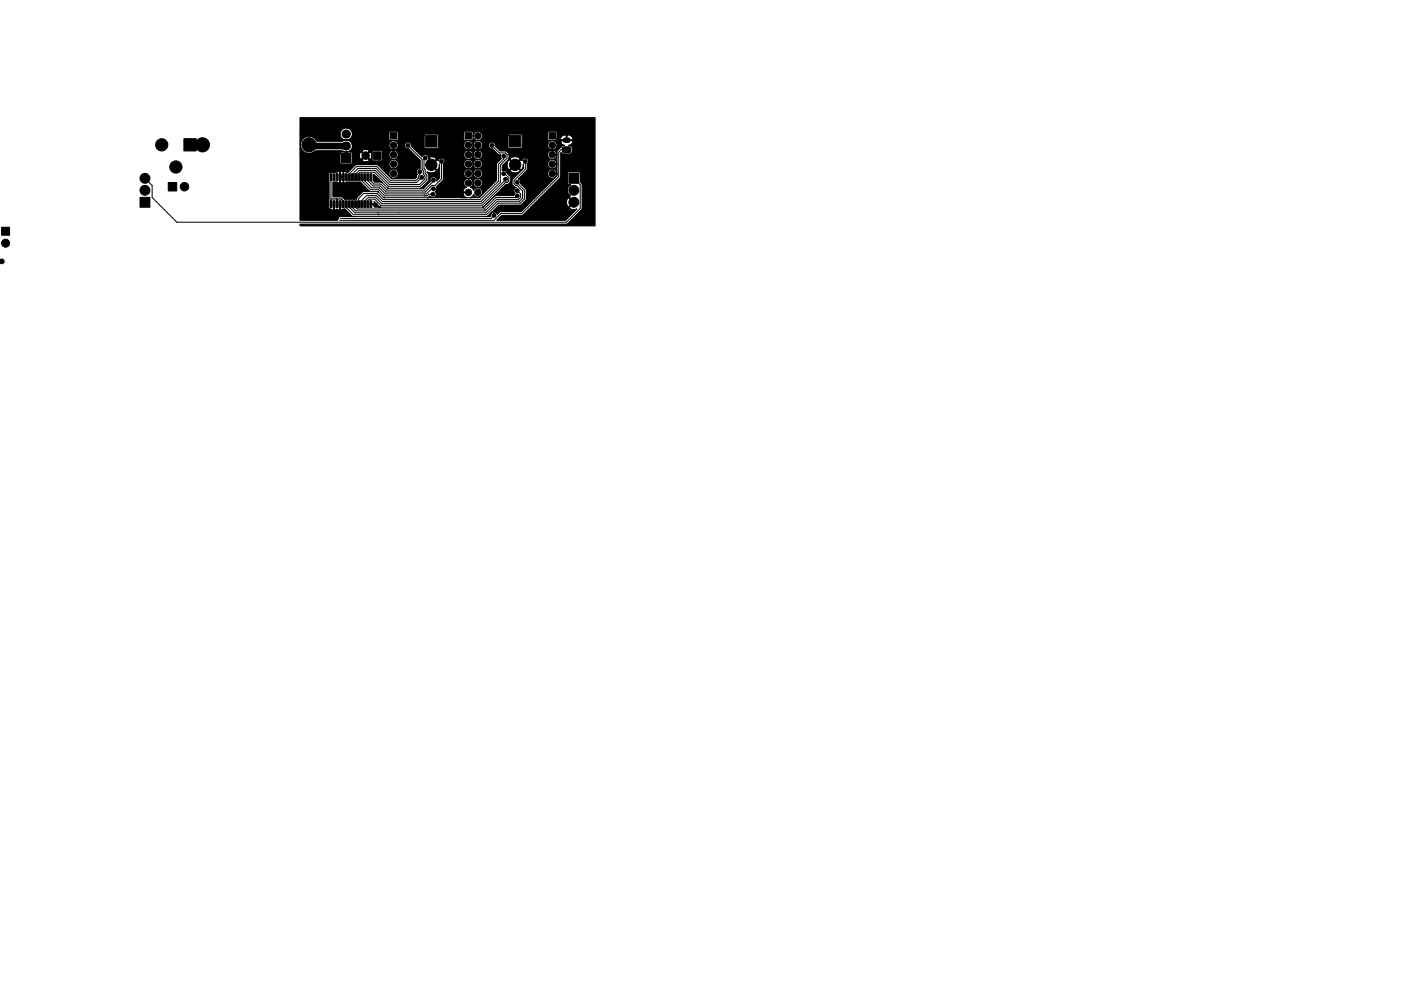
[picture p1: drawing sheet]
<svg xmlns="http://www.w3.org/2000/svg" width="297mm" height="210mm" viewBox="0 0 297 210" stroke-linecap="round" stroke-linejoin="round" font-family="sans-serif">
<g fill="#000" stroke="#000" stroke-width=".21">
<path d="M39 29.4h2.6v2.6h-2.6zM70 36.9h.4l-.1 1.4-.3-.1zM70.7 36.9h.3l-.1 1.4-.3-.1zM71.3 36.9h.4l-.1 1.4-.3-.1zM72 36.9h.3l-.1 1.4-.3-.1zM72.6 36.9h.4l-.1 1.4-.3-.1zM73.3 36.9h.3l-.1 1.4-.3-.1zM73.9 36.9h.4l-.1 1.4-.3-.1zM72.4 32.6h2v1.9h-2zM74.6 36.9h.3l-.1 1.4-.3-.1zM75.2 36.9h.4l-.1 1.4-.3-.1zM75.9 36.9h.3l-.1 1.4-.3-.1z"/>
<path d="M76.5 36.9h.4l-.1 1.4-.3-.1zM77.2 36.9h.3l-.1 1.4-.3-.1zM77.8 36.9h.4l-.1 1.4-.3-.1zM78.5 36.9h.3l-.1 1.4-.3-.1zM79.2 32.2h1.6v1.6h-1.6zM79.1 36.9l1.9 1.9-1.6-.2-.3-.3zM82.1 39.8l.3 .1zM82.8 28.1h1.3v1.4h-1.3zM90.2 28.8h2.4v2.4h-2.4zM98.6 28.1h1.4v1.4h-1.4zM108 28.8h2.4v2.4h-2.4zM116.4 28.1h1.4v1.4h-1.4z"/>
<path d="M120.6 36.8h2.1v2.1h-2.1zM119.3 31.2h1.6l.1 1-1.6 .1zM.3 48.2h1.7v1.7h-1.7zM29.7 41.9h2.1v2.1h-2.1zM35.7 38.7h1.8v1.8h-1.8zM70 42.6l.4 .1-.1 1.3h-.3zM70.7 42.6l.3 .1-.1 1.3h-.3zM71.3 42.6l.4 .1-.1 1.3h-.3zM72 42.6l.3 .1-.1 1.3h-.3zM72.6 42.6l.4 .1-.1 1.3h-.3zM73.3 42.6l.3 .1-.1 1.3h-.3zM73.9 42.6l.4 .1-.1 1.3h-.3z"/>
<path d="M74.6 42.6l.3 .1-.1 1.3h-.3zM75.2 42.6l.4 .1-.1 1.3h-.3zM75.9 42.6l.3 .1-.1 1.3h-.3zM76.5 42.6l.4 .1-.1 1.3h-.3zM77.2 42.6l.3 .1-.1 1.3h-.3zM77.8 42.6l.4 .1-.1 1.3h-.3zM78.5 42.6l.3 .1-.1 1.3h-.3zM80 40.6l.2 .2zM78.5 43.2h.7l.1-.5 1.4 1.2h-1.4l-.1-.5h-.7zM81.3 41.8l.2 .1zM63.6 25h62.6v22.9h-62.6v-.4h56.6l3.2-3.2v-5.1l-.4-.6v-1.8l-.1-.3h-2.3l-.2 .1-.1 2.3 .2 .3h.5l-.2 .1a1.35 1.35 0 0 0 .2 2.2l-.3 .3 1.1 1.1-1.1 1.1a1.23 1.23 0 0 0 1.6 .3l-2.4 2.4h-14.6l1.1-1h4.4l2.7-2.7h6.6l.1 .6 .4 .3 .9-1-.9-.9-.4 .4-.1 .6h-6.6l5.3-5.4 .1-5.2 .1-.1 .5 .3h1.5l.3-.4v-.8a.6 .6 0 0 0-.8-.6 .85 .85 0 0 0 .9-1h-2.5l-.1 .2 .2 .5 .8 .3-.6 .1-1.1 1.3v5.1l-7.6 7.6h-4.4l-.7 .6a.7 .7 0 0 0-.8-.5 .7 .7 0 0 0-.5 .8l-.9 .1 2.6-2.4h4.6l1.1-1 .1-.3v-2l-1.3-1.3a.7 .7 0 0 0-.4-.9l1.2-1.3h5a.98 .98 0 0 0 1.3 1 .98 .98 0 0 0 .4-1.6 .98 .98 0 0 0-1.6 .4l-.1 .2h-5l.7-.6 .1-1.4h4.2a.98 .98 0 0 0 1.3 1 .98 .98 0 0 0 .4-1.6 .98 .98 0 0 0-1.6 .4l-.1 .2h-4.2a.7 .7 0 0 0-.2-1.1 .7 .7 0 0 0-1 .5l-.3-.2-1 1.1 1 1a1.12 1.12 0 0 0 .5-1.2l.1 .9-2.4 2.5v1l.5 .5 .4 .1a.7 .7 0 0 0-.3 1.2l-.2 .5h-4l-2.5 2.4h-.2l5-4.8h.4l.5-.5v-1.1l-1-1.2-.3-.1h1.3a1.31 1.31 0 0 0 2.1 0l-1.1-1.1-1 1.1h-1.7v-1l.2-.2h.8a1.02 1.02 0 0 0 .5 1l1.1-1-1.1-1.1a1.09 1.09 0 0 0-.5 1.1h-.8l1.2-1.2h.3l1 1 1.1-1a1.31 1.31 0 0 0-2.1 0h-.3v-1.1h8.2a.98 .98 0 0 0 1.3 1 .98 .98 0 0 0 .4-1.6 .98 .98 0 0 0-1.6 .4l-.1 .2h-8.2l-.6-.6-1.3-.1-1-1a.7 .7 0 0 0-.7-.8 .7 .7 0 0 0-.7 .7 .7 .7 0 0 0 .8 .6l1.2 1.3h.6l-.1 .4 .2 .4-1 1.2v3.5l-3.7 3.6h-2l.8-.6a.98 .98 0 0 0 1.6 .3 .98 .98 0 0 0-.1-1.6 .98 .98 0 0 0-1.5 .4l-.2-.4-.5-.3a1.12 1.12 0 0 0 .6-1 .98 .98 0 0 0 1.4 1 .98 .98 0 0 0 .3-1.6 .98 .98 0 0 0-1.6 .4l-.1 .2a.98 .98 0 0 0-1.6-.7 .98 .98 0 0 0 .2 1.7l-.5 .3-.2 .5 .1 .2h1.1v.2h-1.1l-.1 .2 .2 .5 .6 .3h-8.4l.5-.3h.2a.7 .7 0 0 0 1 .1 .7 .7 0 0 0-.1-1 .88 .88 0 0 0 .3-1.1l1.5-1.5v-1.4h4.3a.98 .98 0 0 0 1 1.1 .98 .98 0 0 0 1-1.1 1.1 1.1 0 0 0 .9 1.1 .99 .99 0 0 0 1.1-.9 .99 .99 0 0 0-.9-1.1 .99 .99 0 0 0-1.1 .9 .98 .98 0 0 0-1-.9 .98 .98 0 0 0-1 .9h-4.3v-1.9l4.3-.1v.2a.98 .98 0 0 0 1.1 .9 .98 .98 0 0 0 .9-1.1 1.1 1.1 0 0 0 .9 1.1 .99 .99 0 0 0 1.1-.9 .99 .99 0 0 0-.9-1.1 .99 .99 0 0 0-1.1 .9 .98 .98 0 0 0-1-.9 .98 .98 0 0 0-1 .9h-4.2a.7 .7 0 0 0-.2-1.1 .7 .7 0 0 0-1 .5l-.3-.2-1 1.1 1 1a1.12 1.12 0 0 0 .5-1.2l.1 3-.6 .6a.7 .7 0 0 0-.7-.9 .7 .7 0 0 0-.6 1l-1.5 1.4h-.7l1.8-1.6v-1.2l-.4-.7 .6 .2h.7l.6-.2 .1-.2-1.2-1.2 1.2-1.2-.1-.3-.7-.2h-.9a.7 .7 0 0 0-.6-.5 .7 .7 0 0 0-.7 .5l-.6-.6h9.4a.98 .98 0 0 0 1 1.1 .98 .98 0 0 0 1-1.1 1.1 1.1 0 0 0 .9 1.1 .99 .99 0 0 0 1.1-.9 .99 .99 0 0 0-.9-1.1 .99 .99 0 0 0-1.1 .9 .98 .98 0 0 0-1-.9 .98 .98 0 0 0-1 .9h-9.4l-1.7-1.7a.7 .7 0 0 0-.7-.8 .7 .7 0 0 0-.7 .7 .7 .7 0 0 0 .8 .6l2.5 2.5v1.8a.7 .7 0 0 0-.7 .3 .7 .7 0 0 0 .1 .9l-.2 .2v.4l-.3 .3h-4.9l-1.3-1.2h.7v.2a.98 .98 0 0 0 1.5 .8 .98 .98 0 0 0 0-1.7 .98 .98 0 0 0-1.5 .7h-.7l-1.9-1.8-4.4 .1-1.8 1.6-.7-.3-.1 .2v2.2l.1 .1 .7-.2h2.6l2.3 2-1.7 .1-1.2 1.2-.1 .4h-2.5l-.7-.5h-1.8v-3.2h.5l.8 .2 .2-.5a.39 .39 0 0 0 .3 .5 .39 .39 0 0 0 .4-.5l-.1-.6h-.5l-.2 .6v-.6v-.8l.2 .6h.5l.1-.7a.38 .38 0 0 0-.4-.4 .38 .38 0 0 0-.3 .5l-.2-.6-.8 .3h-1.1l-.3 .3v7.1l.2 .3 .7 .2 .1-.1v-1.2h.2v1.2l.3 .1a.41 .41 0 0 1 .7 0l.1-.1v-1.2h.2v1.2l.2 .1 .7-.2 1.8 1.6-2.8 .1-.3 .1-.2 .6h-8v-14.1h8.5v1.9l.2 .3 10.2-.1a.98 .98 0 0 0 1.3 1 .98 .98 0 0 0 .3-1.6 .98 .98 0 0 0-1.6 .4v.2h-7.9l.1-.8h2a.92 .92 0 0 0 1.6 0l-.8-.7-.8 .7h-2v-.8h1.5l.2 .6 .2 .1 .8-.8h.3l.7 .8a.92 .92 0 0 0 0-1.5l-.7 .7h-.3l-.8-.7h-.2l-.2 .8h-1.5v-.6l-.3-.2h-2.1l-.2 .3h-8.5v-2h.1v.3a1.8 1.8 0 0 0 1.2 1.5 1.8 1.8 0 0 0 1.9-.4h5.8l.7 .2 3.4-.1 .8 .8 .7-.7h.7v1.7l.3 .2h1.8l.1-.2v-1.2h1.4v.2a.98 .98 0 0 0 1.5 .8 .98 .98 0 0 0 0-1.7 .98 .98 0 0 0-1.5 .7h-1.4v-.6l-.3-.2h-1.6l-.3 .3h-.7v-.3l-.7-.2-.7 .2-.1 .2h-2.7a1.25 1.25 0 0 0 .7-1.4h7.8v.2a.98 .98 0 0 0 1.5 .8 .98 .98 0 0 0 0-1.7 .98 .98 0 0 0-1.5 .7h-7.8l-.1-.2a1.33 1.33 0 0 0-2-.5l-5.5-.1a1.81 1.81 0 0 0-1.9-.9 1.81 1.81 0 0 0-1.5 1.6h-.1v-2.2h8.5v.3a1.3 1.3 0 0 0 1.6 1 1.3 1.3 0 0 0 1-1.6h7.8v1.5l.3 .2 1.5-.1 .1-.9h5.5v2.4l.3 .3h2.5l.2-.2v-.6h5.4v.2a.98 .98 0 0 0 1.1 .9 .98 .98 0 0 0 .9-1.1 1.1 1.1 0 0 0 .9 1.1 .99 .99 0 0 0 1.1-.9 .99 .99 0 0 0-.9-1.1 .99 .99 0 0 0-1.1 .9 .98 .98 0 0 0-1-.9 .98 .98 0 0 0-1 .9h-5.4v-2l-.2-.2h-2.5l-.3 .3h-5.5v-.7h13.9v1.5l.3 .2 1.6-.1 .1-1a.98 .98 0 0 0 1 1.1 .98 .98 0 0 0 1-1h5.4v2.4l.3 .3h2.5l.2-.2v-.6h5.4v.2a.98 .98 0 0 0 1.5 .8 .98 .98 0 0 0 0-1.7 .98 .98 0 0 0-1.5 .7h-5.4v-2l-.2-.2h-2.5l-.3 .3h-5.4l-.3-.7h14.1v1.5l.3 .2h1.4l.3-.3 1.9 .1v-1h.2v1h1.2a1 1 0 0 0-1.4-1 1.11 1.11 0 0 0-1.2 .9h-.7v-1.4l-.3-.3-1.4 .1-.3 .2h-14.1a1.02 1.02 0 0 0-1-.2 1.02 1.02 0 0 0-.7 .8v-.7l-.3-.2-1.4 .1-.3 .2h-13.9l-.3-.3-1.4 .1-.2 .2h-7.8l-.1-.1a1.32 1.32 0 0 0-1.4-.8 1.32 1.32 0 0 0-1.1 1.2h-8.5z"/>
<circle cx="30.7" cy="37.8" r="1.05"/>
<circle cx="34.3" cy="30.7" r="1.3"/>
<circle cx="37.3" cy="35.4" r="1.3"/>
<circle cx="39.1" cy="39.6" r=".9"/>
<circle cx="42.9" cy="30.7" r="1.5"/>
<circle cx="65.5" cy="30.7" r="1.5"/>
<circle cx="77.5" cy="33" r=".8"/>
<circle cx="79.6" cy="37.8" r=".4"/>
<circle cx="83.4" cy="30.8" r=".67"/>
<circle cx="83.4" cy="32.8" r=".67"/>
<circle cx="83.4" cy="34.8" r=".67"/>
<circle cx="83.4" cy="36.8" r=".67"/>
<circle cx="85.5" cy="30" r=".4"/>
<circle cx="86.5" cy="30.9" r=".4"/>
<circle cx="89" cy="36.4" r=".4"/>
<circle cx="89.4" cy="37.6" r=".4"/>
<circle cx="90.2" cy="33.5" r=".4"/>
<circle cx="91.4" cy="35" r="1.2"/>
<circle cx="91.9" cy="38.2" r=".4"/>
<circle cx="93.6" cy="34.2" r=".4"/>
<circle cx="99.3" cy="30.8" r=".67"/>
<circle cx="99.3" cy="32.8" r=".67"/>
<circle cx="99.3" cy="34.8" r=".67"/>
<circle cx="99.3" cy="38.8" r=".67"/>
<circle cx="99.3" cy="36.8" r=".67"/>
<circle cx="101.3" cy="30.8" r=".67"/>
<circle cx="101.3" cy="28.8" r=".67"/>
<circle cx="101.3" cy="32.8" r=".67"/>
<circle cx="101.3" cy="34.8" r=".67"/>
<circle cx="101.3" cy="38.8" r=".67"/>
<circle cx="101.3" cy="36.8" r=".67"/>
<circle cx="103.1" cy="31.4" r=".4"/>
<circle cx="104.3" cy="30.9" r=".4"/>
<circle cx="106.8" cy="36.8" r=".4"/>
<circle cx="106.8" cy="33.1" r=".4"/>
<circle cx="107.2" cy="38" r=".4"/>
<circle cx="109.2" cy="35" r="1.2"/>
<circle cx="109.7" cy="38.6" r=".4"/>
<circle cx="111.4" cy="34.2" r=".4"/>
<circle cx="117.1" cy="30.8" r=".67"/>
<circle cx="117.1" cy="32.8" r=".67"/>
<circle cx="117.1" cy="34.8" r=".67"/>
<circle cx="117.1" cy="36.8" r=".67"/>
<circle cx=".4" cy="55.5" r=".48"/>
<circle cx="1.2" cy="51.6" r=".85"/>
<circle cx="30.7" cy="40.4" r="1.05"/>
<circle cx="79.6" cy="43.4" r=".4"/>
<circle cx="91.8" cy="41.2" r=".4"/>
<circle cx="91.9" cy="40" r=".4"/>
<circle cx="93.5" cy="40.8" r=".4"/>
<circle cx="99.3" cy="40.8" r=".67"/>
<circle cx="101.3" cy="40.8" r=".67"/>
<circle cx="104.8" cy="45.7" r=".4"/>
<circle cx="106.3" cy="46.3" r=".4"/>
<circle cx="108.6" cy="40.9" r=".4"/>
<circle cx="109.7" cy="41.5" r=".4"/>
<circle cx="109.7" cy="40.4" r=".4"/>
<circle cx="121.7" cy="42.9" r="1.05"/>
<circle cx="121.7" cy="40.4" r="1.05"/>
</g>
<path d="M73.4 28.4h.1M73.4 31h.1" fill="none" stroke="#000" stroke-width="1.9"/>
<path d="M119.9 29.7h.5" fill="none" stroke="#000" stroke-width="1.2"/>
<g fill="none" stroke="#000" stroke-width=".21">
<path d="M30.7 37.8l1.6 1.6v2.5l5.2 5.2h82.6l2.9-2.9v-5l-1.3-1.4M70.2 37.6v5.7M74.7 37.6v-.7l1.2-1.2h3.8l3 3h5.6l1.1-1.1M76.7 37.6v.7l1.9 1.9h1.7l1.3 1.3h9l.3-.3h.9M77.3 37.6v.8l1.5 1.4h1.6l1.3 1.3h8.7l1.1-1.1h.4M78 37.6v.7l1.1 1.1h1.5l1.3 1.3h8.3l1.4-1.4M78.6 37.6v.8l.7 .6h1.5l1.3 1.3h7.9l1.9-1.9v-.2M79.6 37.8h.5l2.1 2.1h7.6M86.5 30.9l3 3v2l.2 .3v.7l.4 .4v.7l-1.2 1.1h-6.3l-3-3h-3.4l-.8 .8v.7M89 36.4v.6l-.3 .3v.5l-.6 .5h-5.2l-3-3h-4.3l-1.5 1.5v.8M90.2 33.5l-.3 .3v2l.2 .2v.8l.4 .3v1l-1.4 1.4h-6.7l-3-3h-3.1l-.3 .3v.8M90.9 34.4l.5 .6"/>
<path d="M91.4 35v.4M91.5 34.9l-.1 .1M91.6 39.3h.1M93.6 34.2v3.8l-1.4 1.3h-.6M104.3 30.9l1.6 1.5h1.2l.4 .4v.8l-1.4 1.4v3.7l-4.1 4h-20.9l-1.3-1.3h-2l-1.1 1.2v.7M106.8 36.8h.2l.9 .9v.7l-.4 .3h-.4l-4.8 4.8h-21.6l-1.3-1.3h-1.1l-.3 .4v.7M106.8 33.1v.6l-1.1 1.2v3.6l-3.9 3.8h-20.6l-1.3-1.3h-2.8l-1.1 1.1v1.2M107.2 38l-5 5.1h-21.3l-1.3-1.3h-1.5l-.8 .9v.6M107.3 39.1l-4.8 4.8h-22.4l-.5-.5h-.8l-.2-.1M108.7 34.4l.5 .6M109.2 35v.4l-.5 .6M109.3 34.9l-.1 .1"/>
<path d="M109.7 38.6v.2l1.5 1.5v1.9l-.9 .9h-4.7l-2.4 2.4h-28.3l-1.5-1.5v-.7M111.4 34.2v1.7l-2.4 2.4v.7l.3 .3h.3l1.2 1.2v1.6l-.7 .6h-4.7M120.1 29.7h-1.1v.7l-.9 .9v6l-7.6 7.6h-6.1l-1.1 1h-28.5M120.1 31.7h-1.1l-.5 .6v5.2l-7.9 7.8h-4.4l-1.4 1.4h-32.8M75.4 43.3v.7l.4 .3h26.9M78.4 40.6h1.7l1.3 1.3h10M80 45.1h.1M80.2 45.5h.1M89.9 41.5h.1M97.8 41.9h2.5M102.7 44.3h.1M103.1 44.5h.1"/>
<path d="M104.8 45.7l-.7 .6h-32M105.4 42.7l-2.4 2.4h-27.7l-1.2-1.1v-.7M105.4 42.7h.1M109.7 41.6l-.4 .3h-4.2l-2.4 2.4M109.7 41.5v.1M109.7 40.4l.7 .7v.8l-.4 .4h-4.7l-2.5 2.4h-27.4l-.7-.7v-.7"/>
</g>
<path d="M91 33.1v1.4l.4 .5" fill="none" stroke="#000" stroke-width=".5"/>
<path d="M70.2 42.2h2.2l.4 .4v.7M71.4 42.2l.1 1.1" fill="none" stroke="#000" stroke-width=".25"/>
<path d="M40.3 30.7h2.6" fill="none" stroke="#000" stroke-width="2"/>
<path d="M65.5 30.7l.3 .3h7.6" fill="none" stroke="#000" stroke-width="1.4"/>
</svg>
